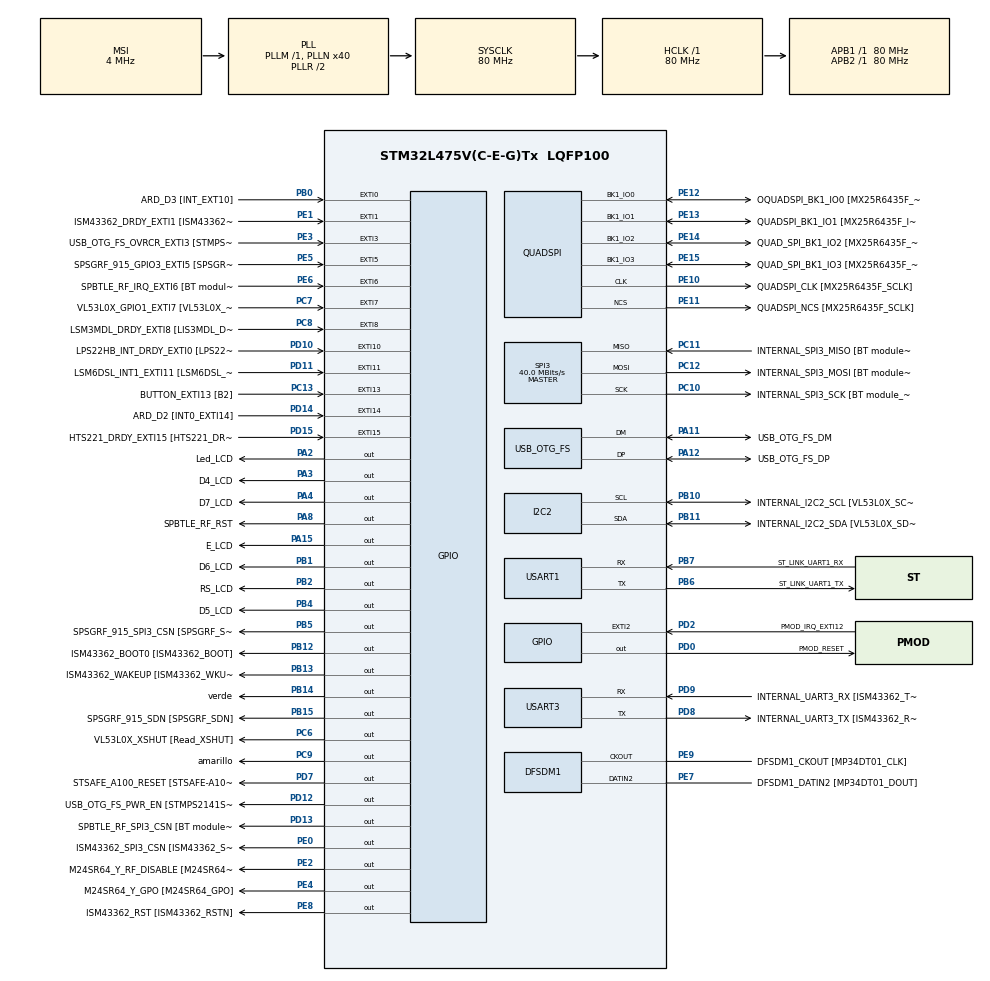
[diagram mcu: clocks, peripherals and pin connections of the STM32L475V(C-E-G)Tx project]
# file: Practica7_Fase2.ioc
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FREERTOS.Tasks01=defaultTask,24,128,StartDefaultTask,Default,NULL,Dynamic,NULL,NULL;led_verde,24,128,Start_led_verde,Default,NULL,Dynamic,NULL,NULL;led_amarillo,8,128,Start_led_amarillo,Default,NULL,Dynamic,NULL,NULL;LCDTareaA,8,128,StartLCD_TareaA,Default,NULL,Dynamic,NULL,NULL
I2C2.Timing=0x10909CEC
Mcu.Family=STM32L4
Mcu.Name=STM32L475V(C-E-G)Tx
Mcu.Package=LQFP100
NVIC.EXTI15_10_IRQn=true\:5\:0\:false\:false\:true\:true\:true\:true\:true
NVIC.EXTI9_5_IRQn=true\:5\:0\:false\:false\:true\:true\:true\:true\:true
NVIC.PriorityGroup=NVIC_PRIORITYGROUP_4
PA0.GPIO_Label=ARD_D1 [UART4_TX]
PA0.Signal=UART4_TX
PA1.GPIO_Label=ARD_D0 [UART4_RX]
PA1.Signal=UART4_RX
PA10.GPIO_Label=USB_OTG_FS_ID
PA10.Signal=USB_OTG_FS_ID
PA11.GPIO_Label=USB_OTG_FS_DM
PA11.Mode=Device_Only
PA11.Signal=USB_OTG_FS_DM
PA12.GPIO_Label=USB_OTG_FS_DP
PA12.Mode=Device_Only
PA12.Signal=USB_OTG_FS_DP
PA13\ (JTMS-SWDIO).GPIO_Label=SYS_JTMS_SWDIO
PA13\ (JTMS-SWDIO).Mode=Serial_Wire
PA13\ (JTMS-SWDIO).Signal=SYS_JTMS-SWDIO
PA14\ (JTCK-SWCLK).GPIO_Label=SYS_JTCK_SWCLK
PA14\ (JTCK-SWCLK).Mode=Serial_Wire
PA14\ (JTCK-SWCLK).Signal=SYS_JTCK-SWCLK
PA15\ (JTDI).GPIO_Label=E_LCD
PA15\ (JTDI).Signal=GPIO_Output
PA2.GPIO_Label=Led_LCD
PA2.Signal=GPIO_Output
PA3.GPIO_Label=D4_LCD
PA3.Signal=GPIO_Output
PA4.GPIO_Label=D7_LCD
PA4.Signal=GPIO_Output
PA5.GPIO_Label=ARD_D13 [SPI1_SCK]
PA5.Signal=SPI1_SCK
PA6.GPIO_Label=ARD_D12 [SPI1_MISO]
PA6.Signal=SPI1_MISO
PA7.GPIO_Label=ARD_D11 [SPI1_MOSI]
PA7.Signal=SPI1_MOSI
PA8.GPIO_Label=SPBTLE_RF_RST
PA8.Signal=GPIO_Output
PA9.GPIO_Label=USB_OTG_FS_VBUS [STMPS2141STR_OUT]
PA9.Signal=USB_OTG_FS_VBUS
PB0.GPIO_Label=ARD_D3 [INT_EXT10]
PB0.Signal=GPXTI0
PB1.GPIO_Label=D6_LCD
PB1.Signal=GPIO_Output
PB10.GPIO_Label=INTERNAL_I2C2_SCL [VL53L0X_SCL]
PB10.GPIO_Pu=GPIO_PULLUP
PB10.Mode=I2C
PB10.Signal=I2C2_SCL
PB11.GPIO_Label=INTERNAL_I2C2_SDA [VL53L0X_SDA]
PB11.GPIO_Pu=GPIO_PULLUP
PB11.Mode=I2C
PB11.Signal=I2C2_SDA
PB12.GPIO_Label=ISM43362_BOOT0 [ISM43362_BOOT]
PB12.Signal=GPIO_Output
PB13.GPIO_Label=ISM43362_WAKEUP [ISM43362_WKUP]
PB13.Signal=GPIO_Output
PB14.GPIO_Label=verde
PB14.Signal=GPIO_Output
PB15.GPIO_Label=SPSGRF_915_SDN [SPSGRF_SDN]
PB15.Signal=GPIO_Output
PB2.GPIO_Label=RS_LCD
PB2.Signal=GPIO_Output
PB3\ (JTDO-TRACESWO).GPIO_Label=SYS_JTD0_SWO
PB3\ (JTDO-TRACESWO).Signal=SYS_JTDO-SWO
PB4\ (NJTRST).GPIO_Label=D5_LCD
PB4\ (NJTRST).Signal=GPIO_Output
PB5.GPIO_Label=SPSGRF_915_SPI3_CSN [SPSGRF_SPI_CS]
PB5.PinState=GPIO_PIN_SET
PB5.Signal=GPIO_Output
PB6.GPIO_Label=ST_LINK_UART1_TX
PB6.Mode=Asynchronous
PB6.Signal=USART1_TX
PB7.GPIO_Label=ST_LINK_UART1_RX
PB7.Mode=Asynchronous
PB7.Signal=USART1_RX
PB8.GPIO_Label=ARD_D15 [I2C1_SCL]
PB8.Signal=I2C1_SCL
PB9.GPIO_Label=ARD_D14 [I2C1_SDA]
PB9.Signal=I2C1_SDA
PC0.GPIO_Label=ARD_A5 [ADC]
PC0.Signal=ADCx_IN1
PC1.GPIO_Label=ARD_A4 [ADC]
PC1.Signal=ADCx_IN2
PC10.GPIO_Label=INTERNAL_SPI3_SCK [BT module_SPI_SCLK] [ISM43362_SCK]
PC10.Mode=Full_Duplex_Master
PC10.Signal=SPI3_SCK
PC11.GPIO_Label=INTERNAL_SPI3_MISO [BT module_SPI_MISO] [ISM43362_MISO]
PC11.Mode=Full_Duplex_Master
PC11.Signal=SPI3_MISO
PC12.GPIO_Label=INTERNAL_SPI3_MOSI [BT module_SPI_MOSI] [ISM43362_MOSI]
PC12.Mode=Full_Duplex_Master
PC12.Signal=SPI3_MOSI
PC13.GPIO_Label=BUTTON_EXTI13 [B2]
PC13.GPIO_ModeDefaultEXTI=GPIO_MODE_IT_FALLING
PC13.Signal=GPXTI13
PC14-OSC32_IN\ (PC14).Mode=LSE-External-Oscillator
PC14-OSC32_IN\ (PC14).Signal=RCC_OSC32_IN
PC15-OSC32_OUT\ (PC15).Mode=LSE-External-Oscillator
PC15-OSC32_OUT\ (PC15).Signal=RCC_OSC32_OUT
PC2.GPIO_Label=ARD_A3 [ADC]
PC2.Signal=ADCx_IN3
PC3.GPIO_Label=ARD_A2 [ADC]
PC3.Signal=ADCx_IN4
PC4.GPIO_Label=ARD_A1 [ADC]
PC4.Signal=ADCx_IN13
PC5.GPIO_Label=ARD_A0 [ADC]
PC5.Signal=ADCx_IN14
PC6.GPIO_Label=VL53L0X_XSHUT [Read_XSHUT]
PC6.Signal=GPIO_Output
PC7.GPIO_Label=VL53L0X_GPIO1_EXTI7 [VL53L0X_GPIO1]
PC7.Signal=GPXTI7
PC8.GPIO_Label=LSM3MDL_DRDY_EXTI8 [LIS3MDL_DRDY]
PC8.Signal=GPXTI8
PC9.GPIO_Label=amarillo
PC9.Signal=GPIO_Output
PD0.GPIO_Label=PMOD_RESET
PD0.Signal=GPIO_Output
PD1.GPIO_Label=PMOD_SPI2_SCK
PD1.Signal=SPI2_SCK
PD10.GPIO_Label=LPS22HB_INT_DRDY_EXTI0 [LPS22HB_INT_DRDY] 
PD10.Signal=GPXTI10
PD11.GPIO_Label=LSM6DSL_INT1_EXTI11 [LSM6DSL_INT1]
PD11.Signal=GPXTI11
PD12.GPIO_Label=USB_OTG_FS_PWR_EN [STMPS2141STR_EN]
PD12.Signal=GPIO_Output
PD13.GPIO_Label=SPBTLE_RF_SPI3_CSN [BT module_SPI_CS]
PD13.PinState=GPIO_PIN_SET
PD13.Signal=GPIO_Output
PD14.GPIO_Label=ARD_D2 [INT0_EXTI14]
PD14.Signal=GPXTI14
PD15.GPIO_Label=HTS221_DRDY_EXTI15 [HTS221_DRDY]
PD15.Signal=GPXTI15
PD2.GPIO_Label=PMOD_IRQ_EXTI12
PD2.Signal=GPXTI2
PD3.GPIO_Label=PMOD_UART2_CTS
PD3.Signal=USART2_CTS
PD4.GPIO_Label=PMOD_UART2_RTS
PD4.Signal=USART2_RTS
PD5.GPIO_Label=PMOD_UART2_TX
PD5.Signal=USART2_TX
PD6.GPIO_Label=PMOD_UART2_RX
PD6.Signal=USART2_RX
PD7.GPIO_Label=STSAFE_A100_RESET [STSAFE-A100_RESET]
PD7.Signal=GPIO_Output
PD8.GPIO_Label=INTERNAL_UART3_TX [ISM43362_RX]
PD8.Mode=Asynchronous
PD8.Signal=USART3_TX
PD9.GPIO_Label=INTERNAL_UART3_RX [ISM43362_TX]
PD9.Mode=Asynchronous
PD9.Signal=USART3_RX
PE0.GPIO_Label=ISM43362_SPI3_CSN [ISM43362_SSN]
PE0.PinState=GPIO_PIN_SET
PE0.Signal=GPIO_Output
PE1.GPIO_Label=ISM43362_DRDY_EXTI1 [ISM43362_DATARDY]
PE1.Signal=GPXTI1
PE10.GPIO_Label=QUADSPI_CLK [MX25R6435F_SCLK]
PE10.Mode=Single Bank
PE10.Signal=QUADSPI_CLK
PE11.GPIO_Label=QUADSPI_NCS [MX25R6435F_SCLK]
PE11.Mode=Single Bank
PE11.Signal=QUADSPI_NCS
PE12.GPIO_Label=OQUADSPI_BK1_IO0 [MX25R6435F_IO0]
PE12.Mode=Single Bank
PE12.Signal=QUADSPI_BK1_IO0
PE13.GPIO_Label=QUADSPI_BK1_IO1 [MX25R6435F_IO1]
PE13.Mode=Single Bank
PE13.Signal=QUADSPI_BK1_IO1
PE14.GPIO_Label=QUAD_SPI_BK1_IO2 [MX25R6435F_IO2]
PE14.Mode=Single Bank
PE14.Signal=QUADSPI_BK1_IO2
PE15.GPIO_Label=QUAD_SPI_BK1_IO3 [MX25R6435F_IO3]
PE15.Mode=Single Bank
PE15.Signal=QUADSPI_BK1_IO3
PE2.GPIO_Label=M24SR64_Y_RF_DISABLE [M24SR64_RFDIS]
PE2.Signal=GPIO_Output
PE3.GPIO_Label=USB_OTG_FS_OVRCR_EXTI3 [STMPS2141STR_FAULT]
PE3.Signal=GPXTI3
PE4.GPIO_Label=M24SR64_Y_GPO [M24SR64_GPO]
PE4.Signal=GPIO_Output
PE5.GPIO_Label=SPSGRF_915_GPIO3_EXTI5 [SPSGRF_GPIO_3]
PE5.Signal=GPXTI5
PE6.GPIO_Label=SPBTLE_RF_IRQ_EXTI6 [BT module_SPI_IRQ]
PE6.Signal=GPXTI6
PE7.GPIO_Label=DFSDM1_DATIN2 [MP34DT01_DOUT]
PE7.Signal=S_DATAIN2DFSDM1
PE8.GPIO_Label=ISM43362_RST [ISM43362_RSTN]
PE8.Signal=GPIO_Output
PE9.GPIO_Label=DFSDM1_CKOUT [MP34DT01_CLK]
PE9.Signal=S_CKOUTDFSDM1
ProjectManager.HeapSize=0x200
ProjectManager.StackSize=0x400
ProjectManager.TargetToolchain=STM32CubeIDE
QUADSPI.ClockPrescaler=2
QUADSPI.FifoThreshold=4
QUADSPI.FlashSize=23
QUADSPI.SampleShifting=QSPI_SAMPLE_SHIFTING_HALFCYCLE
RCC.ADCFreq_Value=48000000
RCC.AHBFreq_Value=80000000
RCC.APB1Freq_Value=80000000
RCC.APB1TimFreq_Value=80000000
RCC.APB2Freq_Value=80000000
RCC.APB2TimFreq_Value=80000000
RCC.CortexFreq_Value=80000000
RCC.HCLKFreq_Value=80000000
RCC.HSE_VALUE=8000000
RCC.HSI_VALUE=16000000
RCC.MSI_VALUE=4000000
RCC.PLLN=40
RCC.PLLSAI1N=24
RCC.SYSCLKFreq_VALUE=80000000
RCC.SYSCLKSource=RCC_SYSCLKSOURCE_PLLCLK
RCC.USBFreq_Value=48000000
RCC.VCOOutputFreq_Value=160000000
SH.ADCx_IN1.0=ADC1_IN1
SH.ADCx_IN13.0=ADC1_IN13
SH.ADCx_IN14.0=ADC1_IN14
SH.ADCx_IN2.0=ADC1_IN2
SH.ADCx_IN3.0=ADC1_IN3
SH.ADCx_IN4.0=ADC1_IN4
SH.S_CKOUTDFSDM1.0=DFSDM1_CKOUT,CKOUT
SH.S_CKOUTDFSDM1.1=DFSDM1_CKOUT,PDM_SPI_Input_from_ch12_and_Internal_Clock
SH.S_DATAIN2DFSDM1.0=DFSDM1_DATIN2,PDM_SPI_Input_from_ch12_and_Internal_Clock
SPI3.CalculateBaudRate=40.0 MBits/s
SPI3.Direction=SPI_DIRECTION_2LINES
SPI3.Mode=SPI_MODE_MASTER
SPI3.VirtualType=VM_MASTER
USART1.VirtualMode-Asynchronous=VM_ASYNC
USART3.VirtualMode-Asynchronous=VM_ASYNC
USB_OTG_FS.VirtualMode=Device_Only
VP_FREERTOS_VS_CMSIS_V2.Mode=CMSIS_V2
board=B-L475E-IOT01A2

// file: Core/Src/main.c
/* USER CODE BEGIN Header */
/**
  ******************************************************************************
  * @file           : main.c
  * @brief          : Main program body
  ******************************************************************************
  * @attention
  *
  * Copyright (c) 2024 STMicroelectronics.
  * All rights reserved.
  *
  * This software is licensed under terms that can be found in the LICENSE file
  * in the root directory of this software component.
  * If no LICENSE file comes with this software, it is provided AS-IS.
  *
  ******************************************************************************
  */
/* USER CODE END Header */
#include "main.h"
#include "cmsis_os.h"

DFSDM_Channel_HandleTypeDef hdfsdm1_channel1;

I2C_HandleTypeDef hi2c2;

QSPI_HandleTypeDef hqspi;

SPI_HandleTypeDef hspi3;

UART_HandleTypeDef huart1;
UART_HandleTypeDef huart3;

PCD_HandleTypeDef hpcd_USB_OTG_FS;

/* Definitions for defaultTask */
osThreadId_t defaultTaskHandle;
const osThreadAttr_t defaultTask_attributes = {
  .name = "defaultTask",
  .stack_size = 128 * 4,
  .priority = (osPriority_t) osPriorityNormal,
};
/* Definitions for led_verde */
osThreadId_t led_verdeHandle;
const osThreadAttr_t led_verde_attributes = {
  .name = "led_verde",
  .stack_size = 128 * 4,
  .priority = (osPriority_t) osPriorityNormal,
};
/* Definitions for led_amarillo */
osThreadId_t led_amarilloHandle;
const osThreadAttr_t led_amarillo_attributes = {
  .name = "led_amarillo",
  .stack_size = 128 * 4,
  .priority = (osPriority_t) osPriorityLow,
};

void SystemClock_Config(void);
static void MX_GPIO_Init(void);
static void MX_DFSDM1_Init(void);
static void MX_I2C2_Init(void);
static void MX_QUADSPI_Init(void);
static void MX_SPI3_Init(void);
static void MX_USART1_UART_Init(void);
static void MX_USART3_UART_Init(void);
static void MX_USB_OTG_FS_PCD_Init(void);
void StartDefaultTask(void *argument);
void Start_led_verde(void *argument);
void Start_led_amarillo(void *argument);

int main(void)
{

  /* MCU Configuration--------------------------------------------------------*/

  /* Reset of all peripherals, Initializes the Flash interface and the Systick. */
  HAL_Init();

  /* Configure the system clock */
  SystemClock_Config();

  /* Initialize all configured peripherals */
  MX_GPIO_Init();
  MX_DFSDM1_Init();
  MX_I2C2_Init();
  MX_QUADSPI_Init();
  MX_SPI3_Init();
  MX_USART1_UART_Init();
  MX_USART3_UART_Init();
  MX_USB_OTG_FS_PCD_Init();

  /* Init scheduler */
  osKernelInitialize();

  /* Create the thread(s) */
  /* creation of defaultTask */
  defaultTaskHandle = osThreadNew(StartDefaultTask, NULL, &defaultTask_attributes);

  /* creation of led_verde */
  led_verdeHandle = osThreadNew(Start_led_verde, NULL, &led_verde_attributes);

  /* creation of led_amarillo */
  led_amarilloHandle = osThreadNew(Start_led_amarillo, NULL, &led_amarillo_attributes);

  /* Start scheduler */
  osKernelStart();

  /* We should never get here as control is now taken by the scheduler */
  /* Infinite loop */
  while (1)
  {

  }
}

void SystemClock_Config(void)
{
  RCC_OscInitTypeDef RCC_OscInitStruct = {0};
  RCC_ClkInitTypeDef RCC_ClkInitStruct = {0};

  /** Configure the main internal regulator output voltage
  */
  if (HAL_PWREx_ControlVoltageScaling(PWR_REGULATOR_VOLTAGE_SCALE1) != HAL_OK)
  {
    Error_Handler();
  }

  /** Configure LSE Drive Capability
  */
  HAL_PWR_EnableBkUpAccess();
  __HAL_RCC_LSEDRIVE_CONFIG(RCC_LSEDRIVE_LOW);

  /** Initializes the RCC Oscillators according to the specified parameters
  * in the RCC_OscInitTypeDef structure.
  */
  RCC_OscInitStruct.OscillatorType = RCC_OSCILLATORTYPE_LSE|RCC_OSCILLATORTYPE_MSI;
  RCC_OscInitStruct.LSEState = RCC_LSE_ON;
  RCC_OscInitStruct.MSIState = RCC_MSI_ON;
  RCC_OscInitStruct.MSICalibrationValue = 0;
  RCC_OscInitStruct.MSIClockRange = RCC_MSIRANGE_6;
  RCC_OscInitStruct.PLL.PLLState = RCC_PLL_ON;
  RCC_OscInitStruct.PLL.PLLSource = RCC_PLLSOURCE_MSI;
  RCC_OscInitStruct.PLL.PLLM = 1;
  RCC_OscInitStruct.PLL.PLLN = 40;
  RCC_OscInitStruct.PLL.PLLP = RCC_PLLP_DIV7;
  RCC_OscInitStruct.PLL.PLLQ = RCC_PLLQ_DIV2;
  RCC_OscInitStruct.PLL.PLLR = RCC_PLLR_DIV2;
  if (HAL_RCC_OscConfig(&RCC_OscInitStruct) != HAL_OK)
  {
    Error_Handler();
  }

  /** Initializes the CPU, AHB and APB buses clocks
  */
  RCC_ClkInitStruct.ClockType = RCC_CLOCKTYPE_HCLK|RCC_CLOCKTYPE_SYSCLK
                              |RCC_CLOCKTYPE_PCLK1|RCC_CLOCKTYPE_PCLK2;
  RCC_ClkInitStruct.SYSCLKSource = RCC_SYSCLKSOURCE_PLLCLK;
  RCC_ClkInitStruct.AHBCLKDivider = RCC_SYSCLK_DIV1;
  RCC_ClkInitStruct.APB1CLKDivider = RCC_HCLK_DIV1;
  RCC_ClkInitStruct.APB2CLKDivider = RCC_HCLK_DIV1;

  if (HAL_RCC_ClockConfig(&RCC_ClkInitStruct, FLASH_LATENCY_4) != HAL_OK)
  {
    Error_Handler();
  }

  /** Enable MSI Auto calibration
  */
  HAL_RCCEx_EnableMSIPLLMode();
}

static void MX_DFSDM1_Init(void)
{

  hdfsdm1_channel1.Instance = DFSDM1_Channel1;
  hdfsdm1_channel1.Init.OutputClock.Activation = ENABLE;
  hdfsdm1_channel1.Init.OutputClock.Selection = DFSDM_CHANNEL_OUTPUT_CLOCK_SYSTEM;
  hdfsdm1_channel1.Init.OutputClock.Divider = 2;
  hdfsdm1_channel1.Init.Input.Multiplexer = DFSDM_CHANNEL_EXTERNAL_INPUTS;
  hdfsdm1_channel1.Init.Input.DataPacking = DFSDM_CHANNEL_STANDARD_MODE;
  hdfsdm1_channel1.Init.Input.Pins = DFSDM_CHANNEL_FOLLOWING_CHANNEL_PINS;
  hdfsdm1_channel1.Init.SerialInterface.Type = DFSDM_CHANNEL_SPI_RISING;
  hdfsdm1_channel1.Init.SerialInterface.SpiClock = DFSDM_CHANNEL_SPI_CLOCK_INTERNAL;
  hdfsdm1_channel1.Init.Awd.FilterOrder = DFSDM_CHANNEL_FASTSINC_ORDER;
  hdfsdm1_channel1.Init.Awd.Oversampling = 1;
  hdfsdm1_channel1.Init.Offset = 0;
  hdfsdm1_channel1.Init.RightBitShift = 0x00;
  if (HAL_DFSDM_ChannelInit(&hdfsdm1_channel1) != HAL_OK)
  {
    Error_Handler();
  }

}

static void MX_I2C2_Init(void)
{

  hi2c2.Instance = I2C2;
  hi2c2.Init.Timing = 0x10909CEC;
  hi2c2.Init.OwnAddress1 = 0;
  hi2c2.Init.AddressingMode = I2C_ADDRESSINGMODE_7BIT;
  hi2c2.Init.DualAddressMode = I2C_DUALADDRESS_DISABLE;
  hi2c2.Init.OwnAddress2 = 0;
  hi2c2.Init.OwnAddress2Masks = I2C_OA2_NOMASK;
  hi2c2.Init.GeneralCallMode = I2C_GENERALCALL_DISABLE;
  hi2c2.Init.NoStretchMode = I2C_NOSTRETCH_DISABLE;
  if (HAL_I2C_Init(&hi2c2) != HAL_OK)
  {
    Error_Handler();
  }

  /** Configure Analogue filter
  */
  if (HAL_I2CEx_ConfigAnalogFilter(&hi2c2, I2C_ANALOGFILTER_ENABLE) != HAL_OK)
  {
    Error_Handler();
  }

  /** Configure Digital filter
  */
  if (HAL_I2CEx_ConfigDigitalFilter(&hi2c2, 0) != HAL_OK)
  {
    Error_Handler();
  }

}

static void MX_QUADSPI_Init(void)
{

  /* QUADSPI parameter configuration*/
  hqspi.Instance = QUADSPI;
  hqspi.Init.ClockPrescaler = 2;
  hqspi.Init.FifoThreshold = 4;
  hqspi.Init.SampleShifting = QSPI_SAMPLE_SHIFTING_HALFCYCLE;
  hqspi.Init.FlashSize = 23;
  hqspi.Init.ChipSelectHighTime = QSPI_CS_HIGH_TIME_1_CYCLE;
  hqspi.Init.ClockMode = QSPI_CLOCK_MODE_0;
  if (HAL_QSPI_Init(&hqspi) != HAL_OK)
  {
    Error_Handler();
  }

}

static void MX_SPI3_Init(void)
{

  /* SPI3 parameter configuration*/
  hspi3.Instance = SPI3;
  hspi3.Init.Mode = SPI_MODE_MASTER;
  hspi3.Init.Direction = SPI_DIRECTION_2LINES;
  hspi3.Init.DataSize = SPI_DATASIZE_4BIT;
  hspi3.Init.CLKPolarity = SPI_POLARITY_LOW;
  hspi3.Init.CLKPhase = SPI_PHASE_1EDGE;
  hspi3.Init.NSS = SPI_NSS_SOFT;
  hspi3.Init.BaudRatePrescaler = SPI_BAUDRATEPRESCALER_2;
  hspi3.Init.FirstBit = SPI_FIRSTBIT_MSB;
  hspi3.Init.TIMode = SPI_TIMODE_DISABLE;
  hspi3.Init.CRCCalculation = SPI_CRCCALCULATION_DISABLE;
  hspi3.Init.CRCPolynomial = 7;
  hspi3.Init.CRCLength = SPI_CRC_LENGTH_DATASIZE;
  hspi3.Init.NSSPMode = SPI_NSS_PULSE_ENABLE;
  if (HAL_SPI_Init(&hspi3) != HAL_OK)
  {
    Error_Handler();
  }

}

static void MX_USART1_UART_Init(void)
{

  huart1.Instance = USART1;
  huart1.Init.BaudRate = 115200;
  huart1.Init.WordLength = UART_WORDLENGTH_8B;
  huart1.Init.StopBits = UART_STOPBITS_1;
  huart1.Init.Parity = UART_PARITY_NONE;
  huart1.Init.Mode = UART_MODE_TX_RX;
  huart1.Init.HwFlowCtl = UART_HWCONTROL_NONE;
  huart1.Init.OverSampling = UART_OVERSAMPLING_16;
  huart1.Init.OneBitSampling = UART_ONE_BIT_SAMPLE_DISABLE;
  huart1.AdvancedInit.AdvFeatureInit = UART_ADVFEATURE_NO_INIT;
  if (HAL_UART_Init(&huart1) != HAL_OK)
  {
    Error_Handler();
  }

}

static void MX_USART3_UART_Init(void)
{

  huart3.Instance = USART3;
  huart3.Init.BaudRate = 115200;
  huart3.Init.WordLength = UART_WORDLENGTH_8B;
  huart3.Init.StopBits = UART_STOPBITS_1;
  huart3.Init.Parity = UART_PARITY_NONE;
  huart3.Init.Mode = UART_MODE_TX_RX;
  huart3.Init.HwFlowCtl = UART_HWCONTROL_NONE;
  huart3.Init.OverSampling = UART_OVERSAMPLING_16;
  huart3.Init.OneBitSampling = UART_ONE_BIT_SAMPLE_DISABLE;
  huart3.AdvancedInit.AdvFeatureInit = UART_ADVFEATURE_NO_INIT;
  if (HAL_UART_Init(&huart3) != HAL_OK)
  {
    Error_Handler();
  }

}

static void MX_USB_OTG_FS_PCD_Init(void)
{

  hpcd_USB_OTG_FS.Instance = USB_OTG_FS;
  hpcd_USB_OTG_FS.Init.dev_endpoints = 6;
  hpcd_USB_OTG_FS.Init.speed = PCD_SPEED_FULL;
  hpcd_USB_OTG_FS.Init.phy_itface = PCD_PHY_EMBEDDED;
  hpcd_USB_OTG_FS.Init.Sof_enable = DISABLE;
  hpcd_USB_OTG_FS.Init.low_power_enable = DISABLE;
  hpcd_USB_OTG_FS.Init.lpm_enable = DISABLE;
  hpcd_USB_OTG_FS.Init.battery_charging_enable = DISABLE;
  hpcd_USB_OTG_FS.Init.use_dedicated_ep1 = DISABLE;
  hpcd_USB_OTG_FS.Init.vbus_sensing_enable = DISABLE;
  if (HAL_PCD_Init(&hpcd_USB_OTG_FS) != HAL_OK)
  {
    Error_Handler();
  }

}

static void MX_GPIO_Init(void)
{
  GPIO_InitTypeDef GPIO_InitStruct = {0};

  /* GPIO Ports Clock Enable */
  __HAL_RCC_GPIOE_CLK_ENABLE();
  __HAL_RCC_GPIOC_CLK_ENABLE();
  __HAL_RCC_GPIOA_CLK_ENABLE();
  __HAL_RCC_GPIOB_CLK_ENABLE();
  __HAL_RCC_GPIOD_CLK_ENABLE();

  /*Configure GPIO pin Output Level */
  HAL_GPIO_WritePin(GPIOE, M24SR64_Y_RF_DISABLE_Pin|M24SR64_Y_GPO_Pin|ISM43362_RST_Pin, GPIO_PIN_RESET);

  /*Configure GPIO pin Output Level */
  HAL_GPIO_WritePin(GPIOA, ARD_D10_Pin|SPBTLE_RF_RST_Pin|ARD_D9_Pin, GPIO_PIN_RESET);

  /*Configure GPIO pin Output Level */
  HAL_GPIO_WritePin(GPIOB, ARD_D8_Pin|ISM43362_BOOT0_Pin|ISM43362_WAKEUP_Pin|verde_Pin
                          |SPSGRF_915_SDN_Pin|ARD_D5_Pin, GPIO_PIN_RESET);

  /*Configure GPIO pin Output Level */
  HAL_GPIO_WritePin(GPIOD, USB_OTG_FS_PWR_EN_Pin|PMOD_RESET_Pin|STSAFE_A100_RESET_Pin, GPIO_PIN_RESET);

  /*Configure GPIO pin Output Level */
  HAL_GPIO_WritePin(SPBTLE_RF_SPI3_CSN_GPIO_Port, SPBTLE_RF_SPI3_CSN_Pin, GPIO_PIN_SET);

  /*Configure GPIO pin Output Level */
  HAL_GPIO_WritePin(GPIOC, VL53L0X_XSHUT_Pin|amarillo_Pin, GPIO_PIN_RESET);

  /*Configure GPIO pin Output Level */
  HAL_GPIO_WritePin(SPSGRF_915_SPI3_CSN_GPIO_Port, SPSGRF_915_SPI3_CSN_Pin, GPIO_PIN_SET);

  /*Configure GPIO pin Output Level */
  HAL_GPIO_WritePin(ISM43362_SPI3_CSN_GPIO_Port, ISM43362_SPI3_CSN_Pin, GPIO_PIN_SET);

  /*Configure GPIO pins : M24SR64_Y_RF_DISABLE_Pin M24SR64_Y_GPO_Pin ISM43362_RST_Pin ISM43362_SPI3_CSN_Pin */
  GPIO_InitStruct.Pin = M24SR64_Y_RF_DISABLE_Pin|M24SR64_Y_GPO_Pin|ISM43362_RST_Pin|ISM43362_SPI3_CSN_Pin;
  GPIO_InitStruct.Mode = GPIO_MODE_OUTPUT_PP;
  GPIO_InitStruct.Pull = GPIO_NOPULL;
  GPIO_InitStruct.Speed = GPIO_SPEED_FREQ_LOW;
  HAL_GPIO_Init(GPIOE, &GPIO_InitStruct);

  /*Configure GPIO pins : USB_OTG_FS_OVRCR_EXTI3_Pin SPSGRF_915_GPIO3_EXTI5_Pin SPBTLE_RF_IRQ_EXTI6_Pin ISM43362_DRDY_EXTI1_Pin */
  GPIO_InitStruct.Pin = USB_OTG_FS_OVRCR_EXTI3_Pin|SPSGRF_915_GPIO3_EXTI5_Pin|SPBTLE_RF_IRQ_EXTI6_Pin|ISM43362_DRDY_EXTI1_Pin;
  GPIO_InitStruct.Mode = GPIO_MODE_IT_RISING;
  GPIO_InitStruct.Pull = GPIO_NOPULL;
  HAL_GPIO_Init(GPIOE, &GPIO_InitStruct);

  /*Configure GPIO pin : BUTTON_EXTI13_Pin */
  GPIO_InitStruct.Pin = BUTTON_EXTI13_Pin;
  GPIO_InitStruct.Mode = GPIO_MODE_IT_FALLING;
  GPIO_InitStruct.Pull = GPIO_NOPULL;
  HAL_GPIO_Init(BUTTON_EXTI13_GPIO_Port, &GPIO_InitStruct);

  /*Configure GPIO pins : ARD_A5_Pin ARD_A4_Pin ARD_A3_Pin ARD_A2_Pin
                           ARD_A1_Pin ARD_A0_Pin */
  GPIO_InitStruct.Pin = ARD_A5_Pin|ARD_A4_Pin|ARD_A3_Pin|ARD_A2_Pin
                          |ARD_A1_Pin|ARD_A0_Pin;
  GPIO_InitStruct.Mode = GPIO_MODE_ANALOG_ADC_CONTROL;
  GPIO_InitStruct.Pull = GPIO_NOPULL;
  HAL_GPIO_Init(GPIOC, &GPIO_InitStruct);

  /*Configure GPIO pins : ARD_D1_Pin ARD_D0_Pin */
  GPIO_InitStruct.Pin = ARD_D1_Pin|ARD_D0_Pin;
  GPIO_InitStruct.Mode = GPIO_MODE_AF_PP;
  GPIO_InitStruct.Pull = GPIO_NOPULL;
  GPIO_InitStruct.Speed = GPIO_SPEED_FREQ_VERY_HIGH;
  GPIO_InitStruct.Alternate = GPIO_AF8_UART4;
  HAL_GPIO_Init(GPIOA, &GPIO_InitStruct);

  /*Configure GPIO pins : ARD_D10_Pin SPBTLE_RF_RST_Pin ARD_D9_Pin */
  GPIO_InitStruct.Pin = ARD_D10_Pin|SPBTLE_RF_RST_Pin|ARD_D9_Pin;
  GPIO_InitStruct.Mode = GPIO_MODE_OUTPUT_PP;
  GPIO_InitStruct.Pull = GPIO_NOPULL;
  GPIO_InitStruct.Speed = GPIO_SPEED_FREQ_LOW;
  HAL_GPIO_Init(GPIOA, &GPIO_InitStruct);

  /*Configure GPIO pin : ARD_D4_Pin */
  GPIO_InitStruct.Pin = ARD_D4_Pin;
  GPIO_InitStruct.Mode = GPIO_MODE_AF_PP;
  GPIO_InitStruct.Pull = GPIO_NOPULL;
  GPIO_InitStruct.Speed = GPIO_SPEED_FREQ_LOW;
  GPIO_InitStruct.Alternate = GPIO_AF1_TIM2;
  HAL_GPIO_Init(ARD_D4_GPIO_Port, &GPIO_InitStruct);

  /*Configure GPIO pin : ARD_D7_Pin */
  GPIO_InitStruct.Pin = ARD_D7_Pin;
  GPIO_InitStruct.Mode = GPIO_MODE_ANALOG_ADC_CONTROL;
  GPIO_InitStruct.Pull = GPIO_NOPULL;
  HAL_GPIO_Init(ARD_D7_GPIO_Port, &GPIO_InitStruct);

  /*Configure GPIO pins : ARD_D13_Pin ARD_D12_Pin ARD_D11_Pin */
  GPIO_InitStruct.Pin = ARD_D13_Pin|ARD_D12_Pin|ARD_D11_Pin;
  GPIO_InitStruct.Mode = GPIO_MODE_AF_PP;
  GPIO_InitStruct.Pull = GPIO_NOPULL;
  GPIO_InitStruct.Speed = GPIO_SPEED_FREQ_VERY_HIGH;
  GPIO_InitStruct.Alternate = GPIO_AF5_SPI1;
  HAL_GPIO_Init(GPIOA, &GPIO_InitStruct);

  /*Configure GPIO pin : ARD_D3_Pin */
  GPIO_InitStruct.Pin = ARD_D3_Pin;
  GPIO_InitStruct.Mode = GPIO_MODE_IT_RISING;
  GPIO_InitStruct.Pull = GPIO_NOPULL;
  HAL_GPIO_Init(ARD_D3_GPIO_Port, &GPIO_InitStruct);

  /*Configure GPIO pin : ARD_D6_Pin */
  GPIO_InitStruct.Pin = ARD_D6_Pin;
  GPIO_InitStruct.Mode = GPIO_MODE_ANALOG_ADC_CONTROL;
  GPIO_InitStruct.Pull = GPIO_NOPULL;
  HAL_GPIO_Init(ARD_D6_GPIO_Port, &GPIO_InitStruct);

  /*Configure GPIO pins : ARD_D8_Pin ISM43362_BOOT0_Pin ISM43362_WAKEUP_Pin verde_Pin
                           SPSGRF_915_SDN_Pin ARD_D5_Pin SPSGRF_915_SPI3_CSN_Pin */
  GPIO_InitStruct.Pin = ARD_D8_Pin|ISM43362_BOOT0_Pin|ISM43362_WAKEUP_Pin|verde_Pin
                          |SPSGRF_915_SDN_Pin|ARD_D5_Pin|SPSGRF_915_SPI3_CSN_Pin;
  GPIO_InitStruct.Mode = GPIO_MODE_OUTPUT_PP;
  GPIO_InitStruct.Pull = GPIO_NOPULL;
  GPIO_InitStruct.Speed = GPIO_SPEED_FREQ_LOW;
  HAL_GPIO_Init(GPIOB, &GPIO_InitStruct);

  /*Configure GPIO pins : LPS22HB_INT_DRDY_EXTI0_Pin LSM6DSL_INT1_EXTI11_Pin ARD_D2_Pin HTS221_DRDY_EXTI15_Pin
                           PMOD_IRQ_EXTI12_Pin */
  GPIO_InitStruct.Pin = LPS22HB_INT_DRDY_EXTI0_Pin|LSM6DSL_INT1_EXTI11_Pin|ARD_D2_Pin|HTS221_DRDY_EXTI15_Pin
                          |PMOD_IRQ_EXTI12_Pin;
  GPIO_InitStruct.Mode = GPIO_MODE_IT_RISING;
  GPIO_InitStruct.Pull = GPIO_NOPULL;
  HAL_GPIO_Init(GPIOD, &GPIO_InitStruct);

  /*Configure GPIO pins : USB_OTG_FS_PWR_EN_Pin SPBTLE_RF_SPI3_CSN_Pin PMOD_RESET_Pin STSAFE_A100_RESET_Pin */
  GPIO_InitStruct.Pin = USB_OTG_FS_PWR_EN_Pin|SPBTLE_RF_SPI3_CSN_Pin|PMOD_RESET_Pin|STSAFE_A100_RESET_Pin;
  GPIO_InitStruct.Mode = GPIO_MODE_OUTPUT_PP;
  GPIO_InitStruct.Pull = GPIO_NOPULL;
  GPIO_InitStruct.Speed = GPIO_SPEED_FREQ_LOW;
  HAL_GPIO_Init(GPIOD, &GPIO_InitStruct);

  /*Configure GPIO pins : VL53L0X_XSHUT_Pin amarillo_Pin */
  GPIO_InitStruct.Pin = VL53L0X_XSHUT_Pin|amarillo_Pin;
  GPIO_InitStruct.Mode = GPIO_MODE_OUTPUT_PP;
  GPIO_InitStruct.Pull = GPIO_NOPULL;
  GPIO_InitStruct.Speed = GPIO_SPEED_FREQ_LOW;
  HAL_GPIO_Init(GPIOC, &GPIO_InitStruct);

  /*Configure GPIO pins : VL53L0X_GPIO1_EXTI7_Pin LSM3MDL_DRDY_EXTI8_Pin */
  GPIO_InitStruct.Pin = VL53L0X_GPIO1_EXTI7_Pin|LSM3MDL_DRDY_EXTI8_Pin;
  GPIO_InitStruct.Mode = GPIO_MODE_IT_RISING;
  GPIO_InitStruct.Pull = GPIO_NOPULL;
  HAL_GPIO_Init(GPIOC, &GPIO_InitStruct);

  /*Configure GPIO pin : PMOD_SPI2_SCK_Pin */
  GPIO_InitStruct.Pin = PMOD_SPI2_SCK_Pin;
  GPIO_InitStruct.Mode = GPIO_MODE_AF_PP;
  GPIO_InitStruct.Pull = GPIO_NOPULL;
  GPIO_InitStruct.Speed = GPIO_SPEED_FREQ_VERY_HIGH;
  GPIO_InitStruct.Alternate = GPIO_AF5_SPI2;
  HAL_GPIO_Init(PMOD_SPI2_SCK_GPIO_Port, &GPIO_InitStruct);

  /*Configure GPIO pins : PMOD_UART2_CTS_Pin PMOD_UART2_RTS_Pin PMOD_UART2_TX_Pin PMOD_UART2_RX_Pin */
  GPIO_InitStruct.Pin = PMOD_UART2_CTS_Pin|PMOD_UART2_RTS_Pin|PMOD_UART2_TX_Pin|PMOD_UART2_RX_Pin;
  GPIO_InitStruct.Mode = GPIO_MODE_AF_PP;
  GPIO_InitStruct.Pull = GPIO_NOPULL;
  GPIO_InitStruct.Speed = GPIO_SPEED_FREQ_VERY_HIGH;
  GPIO_InitStruct.Alternate = GPIO_AF7_USART2;
  HAL_GPIO_Init(GPIOD, &GPIO_InitStruct);

  /*Configure GPIO pins : ARD_D15_Pin ARD_D14_Pin */
  GPIO_InitStruct.Pin = ARD_D15_Pin|ARD_D14_Pin;
  GPIO_InitStruct.Mode = GPIO_MODE_AF_OD;
  GPIO_InitStruct.Pull = GPIO_NOPULL;
  GPIO_InitStruct.Speed = GPIO_SPEED_FREQ_VERY_HIGH;
  GPIO_InitStruct.Alternate = GPIO_AF4_I2C1;
  HAL_GPIO_Init(GPIOB, &GPIO_InitStruct);

  /* EXTI interrupt init*/
  HAL_NVIC_SetPriority(EXTI9_5_IRQn, 5, 0);
  HAL_NVIC_EnableIRQ(EXTI9_5_IRQn);

  HAL_NVIC_SetPriority(EXTI15_10_IRQn, 5, 0);
  HAL_NVIC_EnableIRQ(EXTI15_10_IRQn);

}

void StartDefaultTask(void *argument)
{
  for(;;)
  {
    osDelay(1);
  }
}

void Start_led_verde(void *argument)
{
  /* USER CODE BEGIN Start_led_verde */
  /* Infinite loop */
  for(;;)
  {HAL_GPIO_WritePin(verde_GPIO_Port, verde_Pin,1);
    osDelay(300);
    HAL_GPIO_WritePin(verde_GPIO_Port, verde_Pin,0);
        osDelay(300);
  }
  /* USER CODE END Start_led_verde */
}

void Start_led_amarillo(void *argument)
{
  /* USER CODE BEGIN Start_led_amarillo */
  /* Infinite loop */
  for(;;)
  {
	  HAL_GPIO_WritePin(amarillo_GPIO_Port, amarillo_Pin, 1);
	      osDelay(300);
	      HAL_GPIO_WritePin(amarillo_GPIO_Port,amarillo_Pin,0);
	          osDelay(300);
  }
  /* USER CODE END Start_led_amarillo */
}

void Error_Handler(void)
{
  __disable_irq();
  while (1)
  {
  }
}
